VERSION 5.7 ;
  NOWIREEXTENSIONATPIN ON ;
  DIVIDERCHAR "/" ;
  BUSBITCHARS "[]" ;
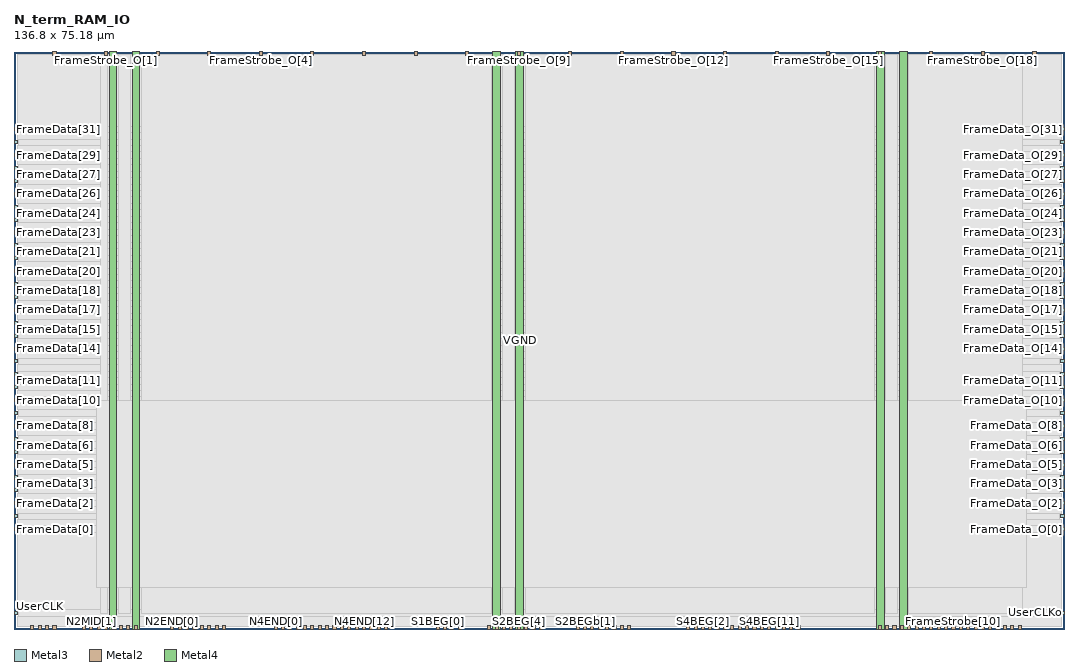
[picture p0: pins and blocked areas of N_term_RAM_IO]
MACRO N_term_RAM_IO
  CLASS BLOCK ;
  FOREIGN N_term_RAM_IO ;
  ORIGIN 0.000 0.000 ;
  SIZE 136.800 BY 75.180 ;
  PIN FrameData[0]
    DIRECTION INPUT ;
    USE SIGNAL ;
    ANTENNAGATEAREA 0.180700 ;
    PORT
      LAYER Metal3 ;
        RECT 0.000 12.820 0.400 13.220 ;
    END
  END FrameData[0]
  PIN FrameData[10]
    DIRECTION INPUT ;
    USE SIGNAL ;
    ANTENNAGATEAREA 0.180700 ;
    PORT
      LAYER Metal3 ;
        RECT 0.000 29.620 0.400 30.020 ;
    END
  END FrameData[10]
  PIN FrameData[11]
    DIRECTION INPUT ;
    USE SIGNAL ;
    ANTENNAGATEAREA 0.180700 ;
    PORT
      LAYER Metal3 ;
        RECT 0.000 31.300 0.400 31.700 ;
    END
  END FrameData[11]
  PIN FrameData[12]
    DIRECTION INPUT ;
    USE SIGNAL ;
    ANTENNAGATEAREA 0.180700 ;
    PORT
      LAYER Metal3 ;
        RECT 0.000 32.980 0.400 33.380 ;
    END
  END FrameData[12]
  PIN FrameData[13]
    DIRECTION INPUT ;
    USE SIGNAL ;
    ANTENNAGATEAREA 0.180700 ;
    PORT
      LAYER Metal3 ;
        RECT 0.000 34.660 0.400 35.060 ;
    END
  END FrameData[13]
  PIN FrameData[14]
    DIRECTION INPUT ;
    USE SIGNAL ;
    ANTENNAGATEAREA 0.180700 ;
    PORT
      LAYER Metal3 ;
        RECT 0.000 36.340 0.400 36.740 ;
    END
  END FrameData[14]
  PIN FrameData[15]
    DIRECTION INPUT ;
    USE SIGNAL ;
    ANTENNAGATEAREA 0.180700 ;
    PORT
      LAYER Metal3 ;
        RECT 0.000 38.020 0.400 38.420 ;
    END
  END FrameData[15]
  PIN FrameData[16]
    DIRECTION INPUT ;
    USE SIGNAL ;
    ANTENNAGATEAREA 0.180700 ;
    PORT
      LAYER Metal3 ;
        RECT 0.000 39.700 0.400 40.100 ;
    END
  END FrameData[16]
  PIN FrameData[17]
    DIRECTION INPUT ;
    USE SIGNAL ;
    ANTENNAGATEAREA 0.180700 ;
    PORT
      LAYER Metal3 ;
        RECT 0.000 41.380 0.400 41.780 ;
    END
  END FrameData[17]
  PIN FrameData[18]
    DIRECTION INPUT ;
    USE SIGNAL ;
    ANTENNAGATEAREA 0.180700 ;
    PORT
      LAYER Metal3 ;
        RECT 0.000 43.060 0.400 43.460 ;
    END
  END FrameData[18]
  PIN FrameData[19]
    DIRECTION INPUT ;
    USE SIGNAL ;
    ANTENNAGATEAREA 0.180700 ;
    PORT
      LAYER Metal3 ;
        RECT 0.000 44.740 0.400 45.140 ;
    END
  END FrameData[19]
  PIN FrameData[1]
    DIRECTION INPUT ;
    USE SIGNAL ;
    ANTENNAGATEAREA 0.180700 ;
    PORT
      LAYER Metal3 ;
        RECT 0.000 14.500 0.400 14.900 ;
    END
  END FrameData[1]
  PIN FrameData[20]
    DIRECTION INPUT ;
    USE SIGNAL ;
    ANTENNAGATEAREA 0.180700 ;
    PORT
      LAYER Metal3 ;
        RECT 0.000 46.420 0.400 46.820 ;
    END
  END FrameData[20]
  PIN FrameData[21]
    DIRECTION INPUT ;
    USE SIGNAL ;
    ANTENNAGATEAREA 0.180700 ;
    PORT
      LAYER Metal3 ;
        RECT 0.000 48.100 0.400 48.500 ;
    END
  END FrameData[21]
  PIN FrameData[22]
    DIRECTION INPUT ;
    USE SIGNAL ;
    ANTENNAGATEAREA 0.180700 ;
    PORT
      LAYER Metal3 ;
        RECT 0.000 49.780 0.400 50.180 ;
    END
  END FrameData[22]
  PIN FrameData[23]
    DIRECTION INPUT ;
    USE SIGNAL ;
    ANTENNAGATEAREA 0.180700 ;
    PORT
      LAYER Metal3 ;
        RECT 0.000 51.460 0.400 51.860 ;
    END
  END FrameData[23]
  PIN FrameData[24]
    DIRECTION INPUT ;
    USE SIGNAL ;
    ANTENNAGATEAREA 0.180700 ;
    PORT
      LAYER Metal3 ;
        RECT 0.000 53.140 0.400 53.540 ;
    END
  END FrameData[24]
  PIN FrameData[25]
    DIRECTION INPUT ;
    USE SIGNAL ;
    ANTENNAGATEAREA 0.180700 ;
    PORT
      LAYER Metal3 ;
        RECT 0.000 54.820 0.400 55.220 ;
    END
  END FrameData[25]
  PIN FrameData[26]
    DIRECTION INPUT ;
    USE SIGNAL ;
    ANTENNAGATEAREA 0.180700 ;
    PORT
      LAYER Metal3 ;
        RECT 0.000 56.500 0.400 56.900 ;
    END
  END FrameData[26]
  PIN FrameData[27]
    DIRECTION INPUT ;
    USE SIGNAL ;
    ANTENNAGATEAREA 0.180700 ;
    PORT
      LAYER Metal3 ;
        RECT 0.000 58.180 0.400 58.580 ;
    END
  END FrameData[27]
  PIN FrameData[28]
    DIRECTION INPUT ;
    USE SIGNAL ;
    ANTENNAGATEAREA 0.180700 ;
    PORT
      LAYER Metal3 ;
        RECT 0.000 59.860 0.400 60.260 ;
    END
  END FrameData[28]
  PIN FrameData[29]
    DIRECTION INPUT ;
    USE SIGNAL ;
    ANTENNAGATEAREA 0.180700 ;
    PORT
      LAYER Metal3 ;
        RECT 0.000 61.540 0.400 61.940 ;
    END
  END FrameData[29]
  PIN FrameData[2]
    DIRECTION INPUT ;
    USE SIGNAL ;
    ANTENNAGATEAREA 0.180700 ;
    PORT
      LAYER Metal3 ;
        RECT 0.000 16.180 0.400 16.580 ;
    END
  END FrameData[2]
  PIN FrameData[30]
    DIRECTION INPUT ;
    USE SIGNAL ;
    ANTENNAGATEAREA 0.180700 ;
    PORT
      LAYER Metal3 ;
        RECT 0.000 63.220 0.400 63.620 ;
    END
  END FrameData[30]
  PIN FrameData[31]
    DIRECTION INPUT ;
    USE SIGNAL ;
    ANTENNAGATEAREA 0.180700 ;
    PORT
      LAYER Metal3 ;
        RECT 0.000 64.900 0.400 65.300 ;
    END
  END FrameData[31]
  PIN FrameData[3]
    DIRECTION INPUT ;
    USE SIGNAL ;
    ANTENNAGATEAREA 0.180700 ;
    PORT
      LAYER Metal3 ;
        RECT 0.000 17.860 0.400 18.260 ;
    END
  END FrameData[3]
  PIN FrameData[4]
    DIRECTION INPUT ;
    USE SIGNAL ;
    ANTENNAGATEAREA 0.180700 ;
    PORT
      LAYER Metal3 ;
        RECT 0.000 19.540 0.400 19.940 ;
    END
  END FrameData[4]
  PIN FrameData[5]
    DIRECTION INPUT ;
    USE SIGNAL ;
    ANTENNAGATEAREA 0.180700 ;
    PORT
      LAYER Metal3 ;
        RECT 0.000 21.220 0.400 21.620 ;
    END
  END FrameData[5]
  PIN FrameData[6]
    DIRECTION INPUT ;
    USE SIGNAL ;
    ANTENNAGATEAREA 0.180700 ;
    PORT
      LAYER Metal3 ;
        RECT 0.000 22.900 0.400 23.300 ;
    END
  END FrameData[6]
  PIN FrameData[7]
    DIRECTION INPUT ;
    USE SIGNAL ;
    ANTENNAGATEAREA 0.180700 ;
    PORT
      LAYER Metal3 ;
        RECT 0.000 24.580 0.400 24.980 ;
    END
  END FrameData[7]
  PIN FrameData[8]
    DIRECTION INPUT ;
    USE SIGNAL ;
    ANTENNAGATEAREA 0.180700 ;
    PORT
      LAYER Metal3 ;
        RECT 0.000 26.260 0.400 26.660 ;
    END
  END FrameData[8]
  PIN FrameData[9]
    DIRECTION INPUT ;
    USE SIGNAL ;
    ANTENNAGATEAREA 0.180700 ;
    PORT
      LAYER Metal3 ;
        RECT 0.000 27.940 0.400 28.340 ;
    END
  END FrameData[9]
  PIN FrameData_O[0]
    DIRECTION OUTPUT ;
    USE SIGNAL ;
    ANTENNADIFFAREA 2.724000 ;
    PORT
      LAYER Metal3 ;
        RECT 136.400 12.820 136.800 13.220 ;
    END
  END FrameData_O[0]
  PIN FrameData_O[10]
    DIRECTION OUTPUT ;
    USE SIGNAL ;
    ANTENNADIFFAREA 2.724000 ;
    PORT
      LAYER Metal3 ;
        RECT 136.400 29.620 136.800 30.020 ;
    END
  END FrameData_O[10]
  PIN FrameData_O[11]
    DIRECTION OUTPUT ;
    USE SIGNAL ;
    ANTENNADIFFAREA 2.724000 ;
    PORT
      LAYER Metal3 ;
        RECT 136.400 31.300 136.800 31.700 ;
    END
  END FrameData_O[11]
  PIN FrameData_O[12]
    DIRECTION OUTPUT ;
    USE SIGNAL ;
    ANTENNADIFFAREA 2.724000 ;
    PORT
      LAYER Metal3 ;
        RECT 136.400 32.980 136.800 33.380 ;
    END
  END FrameData_O[12]
  PIN FrameData_O[13]
    DIRECTION OUTPUT ;
    USE SIGNAL ;
    ANTENNADIFFAREA 2.724000 ;
    PORT
      LAYER Metal3 ;
        RECT 136.400 34.660 136.800 35.060 ;
    END
  END FrameData_O[13]
  PIN FrameData_O[14]
    DIRECTION OUTPUT ;
    USE SIGNAL ;
    ANTENNADIFFAREA 2.724000 ;
    PORT
      LAYER Metal3 ;
        RECT 136.400 36.340 136.800 36.740 ;
    END
  END FrameData_O[14]
  PIN FrameData_O[15]
    DIRECTION OUTPUT ;
    USE SIGNAL ;
    ANTENNADIFFAREA 2.724000 ;
    PORT
      LAYER Metal3 ;
        RECT 136.400 38.020 136.800 38.420 ;
    END
  END FrameData_O[15]
  PIN FrameData_O[16]
    DIRECTION OUTPUT ;
    USE SIGNAL ;
    ANTENNADIFFAREA 2.724000 ;
    PORT
      LAYER Metal3 ;
        RECT 136.400 39.700 136.800 40.100 ;
    END
  END FrameData_O[16]
  PIN FrameData_O[17]
    DIRECTION OUTPUT ;
    USE SIGNAL ;
    ANTENNADIFFAREA 2.724000 ;
    PORT
      LAYER Metal3 ;
        RECT 136.400 41.380 136.800 41.780 ;
    END
  END FrameData_O[17]
  PIN FrameData_O[18]
    DIRECTION OUTPUT ;
    USE SIGNAL ;
    ANTENNADIFFAREA 2.724000 ;
    PORT
      LAYER Metal3 ;
        RECT 136.400 43.060 136.800 43.460 ;
    END
  END FrameData_O[18]
  PIN FrameData_O[19]
    DIRECTION OUTPUT ;
    USE SIGNAL ;
    ANTENNADIFFAREA 2.724000 ;
    PORT
      LAYER Metal3 ;
        RECT 136.400 44.740 136.800 45.140 ;
    END
  END FrameData_O[19]
  PIN FrameData_O[1]
    DIRECTION OUTPUT ;
    USE SIGNAL ;
    ANTENNADIFFAREA 2.724000 ;
    PORT
      LAYER Metal3 ;
        RECT 136.400 14.500 136.800 14.900 ;
    END
  END FrameData_O[1]
  PIN FrameData_O[20]
    DIRECTION OUTPUT ;
    USE SIGNAL ;
    ANTENNADIFFAREA 2.724000 ;
    PORT
      LAYER Metal3 ;
        RECT 136.400 46.420 136.800 46.820 ;
    END
  END FrameData_O[20]
  PIN FrameData_O[21]
    DIRECTION OUTPUT ;
    USE SIGNAL ;
    ANTENNADIFFAREA 2.724000 ;
    PORT
      LAYER Metal3 ;
        RECT 136.400 48.100 136.800 48.500 ;
    END
  END FrameData_O[21]
  PIN FrameData_O[22]
    DIRECTION OUTPUT ;
    USE SIGNAL ;
    ANTENNADIFFAREA 2.724000 ;
    PORT
      LAYER Metal3 ;
        RECT 136.400 49.780 136.800 50.180 ;
    END
  END FrameData_O[22]
  PIN FrameData_O[23]
    DIRECTION OUTPUT ;
    USE SIGNAL ;
    ANTENNADIFFAREA 2.724000 ;
    PORT
      LAYER Metal3 ;
        RECT 136.400 51.460 136.800 51.860 ;
    END
  END FrameData_O[23]
  PIN FrameData_O[24]
    DIRECTION OUTPUT ;
    USE SIGNAL ;
    ANTENNADIFFAREA 2.724000 ;
    PORT
      LAYER Metal3 ;
        RECT 136.400 53.140 136.800 53.540 ;
    END
  END FrameData_O[24]
  PIN FrameData_O[25]
    DIRECTION OUTPUT ;
    USE SIGNAL ;
    ANTENNADIFFAREA 2.724000 ;
    PORT
      LAYER Metal3 ;
        RECT 136.400 54.820 136.800 55.220 ;
    END
  END FrameData_O[25]
  PIN FrameData_O[26]
    DIRECTION OUTPUT ;
    USE SIGNAL ;
    ANTENNADIFFAREA 2.724000 ;
    PORT
      LAYER Metal3 ;
        RECT 136.400 56.500 136.800 56.900 ;
    END
  END FrameData_O[26]
  PIN FrameData_O[27]
    DIRECTION OUTPUT ;
    USE SIGNAL ;
    ANTENNADIFFAREA 2.724000 ;
    PORT
      LAYER Metal3 ;
        RECT 136.400 58.180 136.800 58.580 ;
    END
  END FrameData_O[27]
  PIN FrameData_O[28]
    DIRECTION OUTPUT ;
    USE SIGNAL ;
    ANTENNADIFFAREA 2.724000 ;
    PORT
      LAYER Metal3 ;
        RECT 136.400 59.860 136.800 60.260 ;
    END
  END FrameData_O[28]
  PIN FrameData_O[29]
    DIRECTION OUTPUT ;
    USE SIGNAL ;
    ANTENNADIFFAREA 2.724000 ;
    PORT
      LAYER Metal3 ;
        RECT 136.400 61.540 136.800 61.940 ;
    END
  END FrameData_O[29]
  PIN FrameData_O[2]
    DIRECTION OUTPUT ;
    USE SIGNAL ;
    ANTENNADIFFAREA 2.724000 ;
    PORT
      LAYER Metal3 ;
        RECT 136.400 16.180 136.800 16.580 ;
    END
  END FrameData_O[2]
  PIN FrameData_O[30]
    DIRECTION OUTPUT ;
    USE SIGNAL ;
    ANTENNADIFFAREA 2.724000 ;
    PORT
      LAYER Metal3 ;
        RECT 136.400 63.220 136.800 63.620 ;
    END
  END FrameData_O[30]
  PIN FrameData_O[31]
    DIRECTION OUTPUT ;
    USE SIGNAL ;
    ANTENNADIFFAREA 2.724000 ;
    PORT
      LAYER Metal3 ;
        RECT 136.400 64.900 136.800 65.300 ;
    END
  END FrameData_O[31]
  PIN FrameData_O[3]
    DIRECTION OUTPUT ;
    USE SIGNAL ;
    ANTENNADIFFAREA 2.724000 ;
    PORT
      LAYER Metal3 ;
        RECT 136.400 17.860 136.800 18.260 ;
    END
  END FrameData_O[3]
  PIN FrameData_O[4]
    DIRECTION OUTPUT ;
    USE SIGNAL ;
    ANTENNADIFFAREA 2.724000 ;
    PORT
      LAYER Metal3 ;
        RECT 136.400 19.540 136.800 19.940 ;
    END
  END FrameData_O[4]
  PIN FrameData_O[5]
    DIRECTION OUTPUT ;
    USE SIGNAL ;
    ANTENNADIFFAREA 2.724000 ;
    PORT
      LAYER Metal3 ;
        RECT 136.400 21.220 136.800 21.620 ;
    END
  END FrameData_O[5]
  PIN FrameData_O[6]
    DIRECTION OUTPUT ;
    USE SIGNAL ;
    ANTENNADIFFAREA 2.724000 ;
    PORT
      LAYER Metal3 ;
        RECT 136.400 22.900 136.800 23.300 ;
    END
  END FrameData_O[6]
  PIN FrameData_O[7]
    DIRECTION OUTPUT ;
    USE SIGNAL ;
    ANTENNADIFFAREA 2.724000 ;
    PORT
      LAYER Metal3 ;
        RECT 136.400 24.580 136.800 24.980 ;
    END
  END FrameData_O[7]
  PIN FrameData_O[8]
    DIRECTION OUTPUT ;
    USE SIGNAL ;
    ANTENNADIFFAREA 2.724000 ;
    PORT
      LAYER Metal3 ;
        RECT 136.400 26.260 136.800 26.660 ;
    END
  END FrameData_O[8]
  PIN FrameData_O[9]
    DIRECTION OUTPUT ;
    USE SIGNAL ;
    ANTENNADIFFAREA 2.724000 ;
    PORT
      LAYER Metal3 ;
        RECT 136.400 27.940 136.800 28.340 ;
    END
  END FrameData_O[9]
  PIN FrameStrobe[0]
    DIRECTION INPUT ;
    USE SIGNAL ;
    ANTENNAGATEAREA 0.180700 ;
    PORT
      LAYER Metal2 ;
        RECT 112.600 0.000 113.000 0.400 ;
    END
  END FrameStrobe[0]
  PIN FrameStrobe[10]
    DIRECTION INPUT ;
    USE SIGNAL ;
    ANTENNAGATEAREA 0.180700 ;
    PORT
      LAYER Metal2 ;
        RECT 122.200 0.000 122.600 0.400 ;
    END
  END FrameStrobe[10]
  PIN FrameStrobe[11]
    DIRECTION INPUT ;
    USE SIGNAL ;
    ANTENNAGATEAREA 0.180700 ;
    PORT
      LAYER Metal2 ;
        RECT 123.160 0.000 123.560 0.400 ;
    END
  END FrameStrobe[11]
  PIN FrameStrobe[12]
    DIRECTION INPUT ;
    USE SIGNAL ;
    ANTENNAGATEAREA 0.180700 ;
    PORT
      LAYER Metal2 ;
        RECT 124.120 0.000 124.520 0.400 ;
    END
  END FrameStrobe[12]
  PIN FrameStrobe[13]
    DIRECTION INPUT ;
    USE SIGNAL ;
    ANTENNAGATEAREA 0.180700 ;
    PORT
      LAYER Metal2 ;
        RECT 125.080 0.000 125.480 0.400 ;
    END
  END FrameStrobe[13]
  PIN FrameStrobe[14]
    DIRECTION INPUT ;
    USE SIGNAL ;
    ANTENNAGATEAREA 0.180700 ;
    PORT
      LAYER Metal2 ;
        RECT 126.040 0.000 126.440 0.400 ;
    END
  END FrameStrobe[14]
  PIN FrameStrobe[15]
    DIRECTION INPUT ;
    USE SIGNAL ;
    ANTENNAGATEAREA 0.180700 ;
    PORT
      LAYER Metal2 ;
        RECT 127.000 0.000 127.400 0.400 ;
    END
  END FrameStrobe[15]
  PIN FrameStrobe[16]
    DIRECTION INPUT ;
    USE SIGNAL ;
    ANTENNAGATEAREA 0.180700 ;
    PORT
      LAYER Metal2 ;
        RECT 127.960 0.000 128.360 0.400 ;
    END
  END FrameStrobe[16]
  PIN FrameStrobe[17]
    DIRECTION INPUT ;
    USE SIGNAL ;
    ANTENNAGATEAREA 0.180700 ;
    PORT
      LAYER Metal2 ;
        RECT 128.920 0.000 129.320 0.400 ;
    END
  END FrameStrobe[17]
  PIN FrameStrobe[18]
    DIRECTION INPUT ;
    USE SIGNAL ;
    ANTENNAGATEAREA 0.180700 ;
    PORT
      LAYER Metal2 ;
        RECT 129.880 0.000 130.280 0.400 ;
    END
  END FrameStrobe[18]
  PIN FrameStrobe[19]
    DIRECTION INPUT ;
    USE SIGNAL ;
    ANTENNAGATEAREA 0.180700 ;
    PORT
      LAYER Metal2 ;
        RECT 130.840 0.000 131.240 0.400 ;
    END
  END FrameStrobe[19]
  PIN FrameStrobe[1]
    DIRECTION INPUT ;
    USE SIGNAL ;
    ANTENNAGATEAREA 0.180700 ;
    PORT
      LAYER Metal2 ;
        RECT 113.560 0.000 113.960 0.400 ;
    END
  END FrameStrobe[1]
  PIN FrameStrobe[2]
    DIRECTION INPUT ;
    USE SIGNAL ;
    ANTENNAGATEAREA 0.180700 ;
    PORT
      LAYER Metal2 ;
        RECT 114.520 0.000 114.920 0.400 ;
    END
  END FrameStrobe[2]
  PIN FrameStrobe[3]
    DIRECTION INPUT ;
    USE SIGNAL ;
    ANTENNAGATEAREA 0.180700 ;
    PORT
      LAYER Metal2 ;
        RECT 115.480 0.000 115.880 0.400 ;
    END
  END FrameStrobe[3]
  PIN FrameStrobe[4]
    DIRECTION INPUT ;
    USE SIGNAL ;
    ANTENNAGATEAREA 0.180700 ;
    PORT
      LAYER Metal2 ;
        RECT 116.440 0.000 116.840 0.400 ;
    END
  END FrameStrobe[4]
  PIN FrameStrobe[5]
    DIRECTION INPUT ;
    USE SIGNAL ;
    ANTENNAGATEAREA 0.180700 ;
    PORT
      LAYER Metal2 ;
        RECT 117.400 0.000 117.800 0.400 ;
    END
  END FrameStrobe[5]
  PIN FrameStrobe[6]
    DIRECTION INPUT ;
    USE SIGNAL ;
    ANTENNAGATEAREA 0.180700 ;
    PORT
      LAYER Metal2 ;
        RECT 118.360 0.000 118.760 0.400 ;
    END
  END FrameStrobe[6]
  PIN FrameStrobe[7]
    DIRECTION INPUT ;
    USE SIGNAL ;
    ANTENNAGATEAREA 0.180700 ;
    PORT
      LAYER Metal2 ;
        RECT 119.320 0.000 119.720 0.400 ;
    END
  END FrameStrobe[7]
  PIN FrameStrobe[8]
    DIRECTION INPUT ;
    USE SIGNAL ;
    ANTENNAGATEAREA 0.180700 ;
    PORT
      LAYER Metal2 ;
        RECT 120.280 0.000 120.680 0.400 ;
    END
  END FrameStrobe[8]
  PIN FrameStrobe[9]
    DIRECTION INPUT ;
    USE SIGNAL ;
    ANTENNAGATEAREA 0.180700 ;
    PORT
      LAYER Metal2 ;
        RECT 121.240 0.000 121.640 0.400 ;
    END
  END FrameStrobe[9]
  PIN FrameStrobe_O[0]
    DIRECTION OUTPUT ;
    USE SIGNAL ;
    ANTENNADIFFAREA 2.724000 ;
    PORT
      LAYER Metal2 ;
        RECT 5.080 74.780 5.480 75.180 ;
    END
  END FrameStrobe_O[0]
  PIN FrameStrobe_O[10]
    DIRECTION OUTPUT ;
    USE SIGNAL ;
    ANTENNADIFFAREA 2.724000 ;
    PORT
      LAYER Metal2 ;
        RECT 72.280 74.780 72.680 75.180 ;
    END
  END FrameStrobe_O[10]
  PIN FrameStrobe_O[11]
    DIRECTION OUTPUT ;
    USE SIGNAL ;
    ANTENNADIFFAREA 2.724000 ;
    PORT
      LAYER Metal2 ;
        RECT 79.000 74.780 79.400 75.180 ;
    END
  END FrameStrobe_O[11]
  PIN FrameStrobe_O[12]
    DIRECTION OUTPUT ;
    USE SIGNAL ;
    ANTENNADIFFAREA 2.724000 ;
    PORT
      LAYER Metal2 ;
        RECT 85.720 74.780 86.120 75.180 ;
    END
  END FrameStrobe_O[12]
  PIN FrameStrobe_O[13]
    DIRECTION OUTPUT ;
    USE SIGNAL ;
    ANTENNADIFFAREA 2.724000 ;
    PORT
      LAYER Metal2 ;
        RECT 92.440 74.780 92.840 75.180 ;
    END
  END FrameStrobe_O[13]
  PIN FrameStrobe_O[14]
    DIRECTION OUTPUT ;
    USE SIGNAL ;
    ANTENNADIFFAREA 2.724000 ;
    PORT
      LAYER Metal2 ;
        RECT 99.160 74.780 99.560 75.180 ;
    END
  END FrameStrobe_O[14]
  PIN FrameStrobe_O[15]
    DIRECTION OUTPUT ;
    USE SIGNAL ;
    ANTENNADIFFAREA 2.724000 ;
    PORT
      LAYER Metal2 ;
        RECT 105.880 74.780 106.280 75.180 ;
    END
  END FrameStrobe_O[15]
  PIN FrameStrobe_O[16]
    DIRECTION OUTPUT ;
    USE SIGNAL ;
    ANTENNADIFFAREA 2.724000 ;
    PORT
      LAYER Metal2 ;
        RECT 112.600 74.780 113.000 75.180 ;
    END
  END FrameStrobe_O[16]
  PIN FrameStrobe_O[17]
    DIRECTION OUTPUT ;
    USE SIGNAL ;
    ANTENNADIFFAREA 2.724000 ;
    PORT
      LAYER Metal2 ;
        RECT 119.320 74.780 119.720 75.180 ;
    END
  END FrameStrobe_O[17]
  PIN FrameStrobe_O[18]
    DIRECTION OUTPUT ;
    USE SIGNAL ;
    ANTENNADIFFAREA 2.724000 ;
    PORT
      LAYER Metal2 ;
        RECT 126.040 74.780 126.440 75.180 ;
    END
  END FrameStrobe_O[18]
  PIN FrameStrobe_O[19]
    DIRECTION OUTPUT ;
    USE SIGNAL ;
    ANTENNADIFFAREA 2.724000 ;
    PORT
      LAYER Metal2 ;
        RECT 132.760 74.780 133.160 75.180 ;
    END
  END FrameStrobe_O[19]
  PIN FrameStrobe_O[1]
    DIRECTION OUTPUT ;
    USE SIGNAL ;
    ANTENNADIFFAREA 2.724000 ;
    PORT
      LAYER Metal2 ;
        RECT 11.800 74.780 12.200 75.180 ;
    END
  END FrameStrobe_O[1]
  PIN FrameStrobe_O[2]
    DIRECTION OUTPUT ;
    USE SIGNAL ;
    ANTENNADIFFAREA 2.724000 ;
    PORT
      LAYER Metal2 ;
        RECT 18.520 74.780 18.920 75.180 ;
    END
  END FrameStrobe_O[2]
  PIN FrameStrobe_O[3]
    DIRECTION OUTPUT ;
    USE SIGNAL ;
    ANTENNADIFFAREA 2.724000 ;
    PORT
      LAYER Metal2 ;
        RECT 25.240 74.780 25.640 75.180 ;
    END
  END FrameStrobe_O[3]
  PIN FrameStrobe_O[4]
    DIRECTION OUTPUT ;
    USE SIGNAL ;
    ANTENNADIFFAREA 2.724000 ;
    PORT
      LAYER Metal2 ;
        RECT 31.960 74.780 32.360 75.180 ;
    END
  END FrameStrobe_O[4]
  PIN FrameStrobe_O[5]
    DIRECTION OUTPUT ;
    USE SIGNAL ;
    ANTENNADIFFAREA 2.724000 ;
    PORT
      LAYER Metal2 ;
        RECT 38.680 74.780 39.080 75.180 ;
    END
  END FrameStrobe_O[5]
  PIN FrameStrobe_O[6]
    DIRECTION OUTPUT ;
    USE SIGNAL ;
    ANTENNADIFFAREA 2.724000 ;
    PORT
      LAYER Metal2 ;
        RECT 45.400 74.780 45.800 75.180 ;
    END
  END FrameStrobe_O[6]
  PIN FrameStrobe_O[7]
    DIRECTION OUTPUT ;
    USE SIGNAL ;
    ANTENNADIFFAREA 2.724000 ;
    PORT
      LAYER Metal2 ;
        RECT 52.120 74.780 52.520 75.180 ;
    END
  END FrameStrobe_O[7]
  PIN FrameStrobe_O[8]
    DIRECTION OUTPUT ;
    USE SIGNAL ;
    ANTENNADIFFAREA 2.724000 ;
    PORT
      LAYER Metal2 ;
        RECT 58.840 74.780 59.240 75.180 ;
    END
  END FrameStrobe_O[8]
  PIN FrameStrobe_O[9]
    DIRECTION OUTPUT ;
    USE SIGNAL ;
    ANTENNADIFFAREA 2.724000 ;
    PORT
      LAYER Metal2 ;
        RECT 65.560 74.780 65.960 75.180 ;
    END
  END FrameStrobe_O[9]
  PIN N1END[0]
    DIRECTION INPUT ;
    USE SIGNAL ;
    ANTENNAGATEAREA 0.180700 ;
    PORT
      LAYER Metal2 ;
        RECT 2.200 0.000 2.600 0.400 ;
    END
  END N1END[0]
  PIN N1END[1]
    DIRECTION INPUT ;
    USE SIGNAL ;
    ANTENNAGATEAREA 0.180700 ;
    PORT
      LAYER Metal2 ;
        RECT 3.160 0.000 3.560 0.400 ;
    END
  END N1END[1]
  PIN N1END[2]
    DIRECTION INPUT ;
    USE SIGNAL ;
    ANTENNAGATEAREA 0.180700 ;
    PORT
      LAYER Metal2 ;
        RECT 4.120 0.000 4.520 0.400 ;
    END
  END N1END[2]
  PIN N1END[3]
    DIRECTION INPUT ;
    USE SIGNAL ;
    ANTENNAGATEAREA 0.180700 ;
    PORT
      LAYER Metal2 ;
        RECT 5.080 0.000 5.480 0.400 ;
    END
  END N1END[3]
  PIN N2END[0]
    DIRECTION INPUT ;
    USE SIGNAL ;
    ANTENNAGATEAREA 0.180700 ;
    PORT
      LAYER Metal2 ;
        RECT 20.440 0.000 20.840 0.400 ;
    END
  END N2END[0]
  PIN N2END[1]
    DIRECTION INPUT ;
    USE SIGNAL ;
    ANTENNAGATEAREA 0.180700 ;
    PORT
      LAYER Metal2 ;
        RECT 21.400 0.000 21.800 0.400 ;
    END
  END N2END[1]
  PIN N2END[2]
    DIRECTION INPUT ;
    USE SIGNAL ;
    ANTENNAGATEAREA 0.180700 ;
    PORT
      LAYER Metal2 ;
        RECT 22.360 0.000 22.760 0.400 ;
    END
  END N2END[2]
  PIN N2END[3]
    DIRECTION INPUT ;
    USE SIGNAL ;
    ANTENNAGATEAREA 0.180700 ;
    PORT
      LAYER Metal2 ;
        RECT 23.320 0.000 23.720 0.400 ;
    END
  END N2END[3]
  PIN N2END[4]
    DIRECTION INPUT ;
    USE SIGNAL ;
    ANTENNAGATEAREA 0.180700 ;
    PORT
      LAYER Metal2 ;
        RECT 24.280 0.000 24.680 0.400 ;
    END
  END N2END[4]
  PIN N2END[5]
    DIRECTION INPUT ;
    USE SIGNAL ;
    ANTENNAGATEAREA 0.180700 ;
    PORT
      LAYER Metal2 ;
        RECT 25.240 0.000 25.640 0.400 ;
    END
  END N2END[5]
  PIN N2END[6]
    DIRECTION INPUT ;
    USE SIGNAL ;
    ANTENNAGATEAREA 0.180700 ;
    PORT
      LAYER Metal2 ;
        RECT 26.200 0.000 26.600 0.400 ;
    END
  END N2END[6]
  PIN N2END[7]
    DIRECTION INPUT ;
    USE SIGNAL ;
    ANTENNAGATEAREA 0.180700 ;
    PORT
      LAYER Metal2 ;
        RECT 27.160 0.000 27.560 0.400 ;
    END
  END N2END[7]
  PIN N2MID[0]
    DIRECTION INPUT ;
    USE SIGNAL ;
    ANTENNAGATEAREA 0.180700 ;
    PORT
      LAYER Metal2 ;
        RECT 8.920 0.000 9.320 0.400 ;
    END
  END N2MID[0]
  PIN N2MID[1]
    DIRECTION INPUT ;
    USE SIGNAL ;
    ANTENNAGATEAREA 0.180700 ;
    PORT
      LAYER Metal2 ;
        RECT 9.880 0.000 10.280 0.400 ;
    END
  END N2MID[1]
  PIN N2MID[2]
    DIRECTION INPUT ;
    USE SIGNAL ;
    ANTENNAGATEAREA 0.180700 ;
    PORT
      LAYER Metal2 ;
        RECT 10.840 0.000 11.240 0.400 ;
    END
  END N2MID[2]
  PIN N2MID[3]
    DIRECTION INPUT ;
    USE SIGNAL ;
    ANTENNAGATEAREA 0.180700 ;
    PORT
      LAYER Metal2 ;
        RECT 11.800 0.000 12.200 0.400 ;
    END
  END N2MID[3]
  PIN N2MID[4]
    DIRECTION INPUT ;
    USE SIGNAL ;
    ANTENNAGATEAREA 0.180700 ;
    PORT
      LAYER Metal2 ;
        RECT 12.760 0.000 13.160 0.400 ;
    END
  END N2MID[4]
  PIN N2MID[5]
    DIRECTION INPUT ;
    USE SIGNAL ;
    ANTENNAGATEAREA 0.180700 ;
    PORT
      LAYER Metal2 ;
        RECT 13.720 0.000 14.120 0.400 ;
    END
  END N2MID[5]
  PIN N2MID[6]
    DIRECTION INPUT ;
    USE SIGNAL ;
    ANTENNAGATEAREA 0.180700 ;
    PORT
      LAYER Metal2 ;
        RECT 14.680 0.000 15.080 0.400 ;
    END
  END N2MID[6]
  PIN N2MID[7]
    DIRECTION INPUT ;
    USE SIGNAL ;
    ANTENNAGATEAREA 0.180700 ;
    PORT
      LAYER Metal2 ;
        RECT 15.640 0.000 16.040 0.400 ;
    END
  END N2MID[7]
  PIN N4END[0]
    DIRECTION INPUT ;
    USE SIGNAL ;
    ANTENNAGATEAREA 0.180700 ;
    PORT
      LAYER Metal2 ;
        RECT 33.880 0.000 34.280 0.400 ;
    END
  END N4END[0]
  PIN N4END[10]
    DIRECTION INPUT ;
    USE SIGNAL ;
    ANTENNAGATEAREA 0.180700 ;
    PORT
      LAYER Metal2 ;
        RECT 43.480 0.000 43.880 0.400 ;
    END
  END N4END[10]
  PIN N4END[11]
    DIRECTION INPUT ;
    USE SIGNAL ;
    ANTENNAGATEAREA 0.180700 ;
    PORT
      LAYER Metal2 ;
        RECT 44.440 0.000 44.840 0.400 ;
    END
  END N4END[11]
  PIN N4END[12]
    DIRECTION INPUT ;
    USE SIGNAL ;
    ANTENNAGATEAREA 0.180700 ;
    PORT
      LAYER Metal2 ;
        RECT 45.400 0.000 45.800 0.400 ;
    END
  END N4END[12]
  PIN N4END[13]
    DIRECTION INPUT ;
    USE SIGNAL ;
    ANTENNAGATEAREA 0.180700 ;
    PORT
      LAYER Metal2 ;
        RECT 46.360 0.000 46.760 0.400 ;
    END
  END N4END[13]
  PIN N4END[14]
    DIRECTION INPUT ;
    USE SIGNAL ;
    ANTENNAGATEAREA 0.180700 ;
    PORT
      LAYER Metal2 ;
        RECT 47.320 0.000 47.720 0.400 ;
    END
  END N4END[14]
  PIN N4END[15]
    DIRECTION INPUT ;
    USE SIGNAL ;
    ANTENNAGATEAREA 0.180700 ;
    PORT
      LAYER Metal2 ;
        RECT 48.280 0.000 48.680 0.400 ;
    END
  END N4END[15]
  PIN N4END[1]
    DIRECTION INPUT ;
    USE SIGNAL ;
    ANTENNAGATEAREA 0.180700 ;
    PORT
      LAYER Metal2 ;
        RECT 34.840 0.000 35.240 0.400 ;
    END
  END N4END[1]
  PIN N4END[2]
    DIRECTION INPUT ;
    USE SIGNAL ;
    ANTENNAGATEAREA 0.180700 ;
    PORT
      LAYER Metal2 ;
        RECT 35.800 0.000 36.200 0.400 ;
    END
  END N4END[2]
  PIN N4END[3]
    DIRECTION INPUT ;
    USE SIGNAL ;
    ANTENNAGATEAREA 0.180700 ;
    PORT
      LAYER Metal2 ;
        RECT 36.760 0.000 37.160 0.400 ;
    END
  END N4END[3]
  PIN N4END[4]
    DIRECTION INPUT ;
    USE SIGNAL ;
    ANTENNAGATEAREA 0.180700 ;
    PORT
      LAYER Metal2 ;
        RECT 37.720 0.000 38.120 0.400 ;
    END
  END N4END[4]
  PIN N4END[5]
    DIRECTION INPUT ;
    USE SIGNAL ;
    ANTENNAGATEAREA 0.180700 ;
    PORT
      LAYER Metal2 ;
        RECT 38.680 0.000 39.080 0.400 ;
    END
  END N4END[5]
  PIN N4END[6]
    DIRECTION INPUT ;
    USE SIGNAL ;
    ANTENNAGATEAREA 0.180700 ;
    PORT
      LAYER Metal2 ;
        RECT 39.640 0.000 40.040 0.400 ;
    END
  END N4END[6]
  PIN N4END[7]
    DIRECTION INPUT ;
    USE SIGNAL ;
    ANTENNAGATEAREA 0.180700 ;
    PORT
      LAYER Metal2 ;
        RECT 40.600 0.000 41.000 0.400 ;
    END
  END N4END[7]
  PIN N4END[8]
    DIRECTION INPUT ;
    USE SIGNAL ;
    ANTENNAGATEAREA 0.180700 ;
    PORT
      LAYER Metal2 ;
        RECT 41.560 0.000 41.960 0.400 ;
    END
  END N4END[8]
  PIN N4END[9]
    DIRECTION INPUT ;
    USE SIGNAL ;
    ANTENNAGATEAREA 0.180700 ;
    PORT
      LAYER Metal2 ;
        RECT 42.520 0.000 42.920 0.400 ;
    END
  END N4END[9]
  PIN S1BEG[0]
    DIRECTION OUTPUT ;
    USE SIGNAL ;
    ANTENNADIFFAREA 2.724000 ;
    PORT
      LAYER Metal2 ;
        RECT 55.000 0.000 55.400 0.400 ;
    END
  END S1BEG[0]
  PIN S1BEG[1]
    DIRECTION OUTPUT ;
    USE SIGNAL ;
    ANTENNADIFFAREA 2.724000 ;
    PORT
      LAYER Metal2 ;
        RECT 55.960 0.000 56.360 0.400 ;
    END
  END S1BEG[1]
  PIN S1BEG[2]
    DIRECTION OUTPUT ;
    USE SIGNAL ;
    ANTENNADIFFAREA 2.724000 ;
    PORT
      LAYER Metal2 ;
        RECT 56.920 0.000 57.320 0.400 ;
    END
  END S1BEG[2]
  PIN S1BEG[3]
    DIRECTION OUTPUT ;
    USE SIGNAL ;
    ANTENNADIFFAREA 2.724000 ;
    PORT
      LAYER Metal2 ;
        RECT 57.880 0.000 58.280 0.400 ;
    END
  END S1BEG[3]
  PIN S2BEG[0]
    DIRECTION OUTPUT ;
    USE SIGNAL ;
    ANTENNADIFFAREA 2.724000 ;
    PORT
      LAYER Metal2 ;
        RECT 61.720 0.000 62.120 0.400 ;
    END
  END S2BEG[0]
  PIN S2BEG[1]
    DIRECTION OUTPUT ;
    USE SIGNAL ;
    ANTENNADIFFAREA 2.724000 ;
    PORT
      LAYER Metal2 ;
        RECT 62.680 0.000 63.080 0.400 ;
    END
  END S2BEG[1]
  PIN S2BEG[2]
    DIRECTION OUTPUT ;
    USE SIGNAL ;
    ANTENNADIFFAREA 2.724000 ;
    PORT
      LAYER Metal2 ;
        RECT 63.640 0.000 64.040 0.400 ;
    END
  END S2BEG[2]
  PIN S2BEG[3]
    DIRECTION OUTPUT ;
    USE SIGNAL ;
    ANTENNADIFFAREA 2.724000 ;
    PORT
      LAYER Metal2 ;
        RECT 64.600 0.000 65.000 0.400 ;
    END
  END S2BEG[3]
  PIN S2BEG[4]
    DIRECTION OUTPUT ;
    USE SIGNAL ;
    ANTENNADIFFAREA 2.724000 ;
    PORT
      LAYER Metal2 ;
        RECT 65.560 0.000 65.960 0.400 ;
    END
  END S2BEG[4]
  PIN S2BEG[5]
    DIRECTION OUTPUT ;
    USE SIGNAL ;
    ANTENNADIFFAREA 2.724000 ;
    PORT
      LAYER Metal2 ;
        RECT 66.520 0.000 66.920 0.400 ;
    END
  END S2BEG[5]
  PIN S2BEG[6]
    DIRECTION OUTPUT ;
    USE SIGNAL ;
    ANTENNADIFFAREA 2.724000 ;
    PORT
      LAYER Metal2 ;
        RECT 67.480 0.000 67.880 0.400 ;
    END
  END S2BEG[6]
  PIN S2BEG[7]
    DIRECTION OUTPUT ;
    USE SIGNAL ;
    ANTENNADIFFAREA 2.724000 ;
    PORT
      LAYER Metal2 ;
        RECT 68.440 0.000 68.840 0.400 ;
    END
  END S2BEG[7]
  PIN S2BEGb[0]
    DIRECTION OUTPUT ;
    USE SIGNAL ;
    ANTENNADIFFAREA 2.724000 ;
    PORT
      LAYER Metal2 ;
        RECT 73.240 0.000 73.640 0.400 ;
    END
  END S2BEGb[0]
  PIN S2BEGb[1]
    DIRECTION OUTPUT ;
    USE SIGNAL ;
    ANTENNADIFFAREA 2.724000 ;
    PORT
      LAYER Metal2 ;
        RECT 74.200 0.000 74.600 0.400 ;
    END
  END S2BEGb[1]
  PIN S2BEGb[2]
    DIRECTION OUTPUT ;
    USE SIGNAL ;
    ANTENNADIFFAREA 2.724000 ;
    PORT
      LAYER Metal2 ;
        RECT 75.160 0.000 75.560 0.400 ;
    END
  END S2BEGb[2]
  PIN S2BEGb[3]
    DIRECTION OUTPUT ;
    USE SIGNAL ;
    ANTENNADIFFAREA 2.724000 ;
    PORT
      LAYER Metal2 ;
        RECT 76.120 0.000 76.520 0.400 ;
    END
  END S2BEGb[3]
  PIN S2BEGb[4]
    DIRECTION OUTPUT ;
    USE SIGNAL ;
    ANTENNADIFFAREA 2.724000 ;
    PORT
      LAYER Metal2 ;
        RECT 77.080 0.000 77.480 0.400 ;
    END
  END S2BEGb[4]
  PIN S2BEGb[5]
    DIRECTION OUTPUT ;
    USE SIGNAL ;
    ANTENNADIFFAREA 2.724000 ;
    PORT
      LAYER Metal2 ;
        RECT 78.040 0.000 78.440 0.400 ;
    END
  END S2BEGb[5]
  PIN S2BEGb[6]
    DIRECTION OUTPUT ;
    USE SIGNAL ;
    ANTENNADIFFAREA 2.724000 ;
    PORT
      LAYER Metal2 ;
        RECT 79.000 0.000 79.400 0.400 ;
    END
  END S2BEGb[6]
  PIN S2BEGb[7]
    DIRECTION OUTPUT ;
    USE SIGNAL ;
    ANTENNADIFFAREA 2.724000 ;
    PORT
      LAYER Metal2 ;
        RECT 79.960 0.000 80.360 0.400 ;
    END
  END S2BEGb[7]
  PIN S4BEG[0]
    DIRECTION OUTPUT ;
    USE SIGNAL ;
    ANTENNADIFFAREA 2.724000 ;
    PORT
      LAYER Metal2 ;
        RECT 87.640 0.000 88.040 0.400 ;
    END
  END S4BEG[0]
  PIN S4BEG[10]
    DIRECTION OUTPUT ;
    USE SIGNAL ;
    ANTENNADIFFAREA 2.724000 ;
    PORT
      LAYER Metal2 ;
        RECT 97.240 0.000 97.640 0.400 ;
    END
  END S4BEG[10]
  PIN S4BEG[11]
    DIRECTION OUTPUT ;
    USE SIGNAL ;
    ANTENNADIFFAREA 2.724000 ;
    PORT
      LAYER Metal2 ;
        RECT 98.200 0.000 98.600 0.400 ;
    END
  END S4BEG[11]
  PIN S4BEG[12]
    DIRECTION OUTPUT ;
    USE SIGNAL ;
    ANTENNADIFFAREA 2.724000 ;
    PORT
      LAYER Metal2 ;
        RECT 99.160 0.000 99.560 0.400 ;
    END
  END S4BEG[12]
  PIN S4BEG[13]
    DIRECTION OUTPUT ;
    USE SIGNAL ;
    ANTENNADIFFAREA 2.724000 ;
    PORT
      LAYER Metal2 ;
        RECT 100.120 0.000 100.520 0.400 ;
    END
  END S4BEG[13]
  PIN S4BEG[14]
    DIRECTION OUTPUT ;
    USE SIGNAL ;
    ANTENNADIFFAREA 2.724000 ;
    PORT
      LAYER Metal2 ;
        RECT 101.080 0.000 101.480 0.400 ;
    END
  END S4BEG[14]
  PIN S4BEG[15]
    DIRECTION OUTPUT ;
    USE SIGNAL ;
    ANTENNADIFFAREA 2.724000 ;
    PORT
      LAYER Metal2 ;
        RECT 102.040 0.000 102.440 0.400 ;
    END
  END S4BEG[15]
  PIN S4BEG[1]
    DIRECTION OUTPUT ;
    USE SIGNAL ;
    ANTENNADIFFAREA 2.724000 ;
    PORT
      LAYER Metal2 ;
        RECT 88.600 0.000 89.000 0.400 ;
    END
  END S4BEG[1]
  PIN S4BEG[2]
    DIRECTION OUTPUT ;
    USE SIGNAL ;
    ANTENNADIFFAREA 2.724000 ;
    PORT
      LAYER Metal2 ;
        RECT 89.560 0.000 89.960 0.400 ;
    END
  END S4BEG[2]
  PIN S4BEG[3]
    DIRECTION OUTPUT ;
    USE SIGNAL ;
    ANTENNADIFFAREA 2.724000 ;
    PORT
      LAYER Metal2 ;
        RECT 90.520 0.000 90.920 0.400 ;
    END
  END S4BEG[3]
  PIN S4BEG[4]
    DIRECTION OUTPUT ;
    USE SIGNAL ;
    ANTENNADIFFAREA 2.724000 ;
    PORT
      LAYER Metal2 ;
        RECT 91.480 0.000 91.880 0.400 ;
    END
  END S4BEG[4]
  PIN S4BEG[5]
    DIRECTION OUTPUT ;
    USE SIGNAL ;
    ANTENNADIFFAREA 2.724000 ;
    PORT
      LAYER Metal2 ;
        RECT 92.440 0.000 92.840 0.400 ;
    END
  END S4BEG[5]
  PIN S4BEG[6]
    DIRECTION OUTPUT ;
    USE SIGNAL ;
    ANTENNADIFFAREA 2.724000 ;
    PORT
      LAYER Metal2 ;
        RECT 93.400 0.000 93.800 0.400 ;
    END
  END S4BEG[6]
  PIN S4BEG[7]
    DIRECTION OUTPUT ;
    USE SIGNAL ;
    ANTENNADIFFAREA 2.724000 ;
    PORT
      LAYER Metal2 ;
        RECT 94.360 0.000 94.760 0.400 ;
    END
  END S4BEG[7]
  PIN S4BEG[8]
    DIRECTION OUTPUT ;
    USE SIGNAL ;
    ANTENNADIFFAREA 2.724000 ;
    PORT
      LAYER Metal2 ;
        RECT 95.320 0.000 95.720 0.400 ;
    END
  END S4BEG[8]
  PIN S4BEG[9]
    DIRECTION OUTPUT ;
    USE SIGNAL ;
    ANTENNADIFFAREA 2.724000 ;
    PORT
      LAYER Metal2 ;
        RECT 96.280 0.000 96.680 0.400 ;
    END
  END S4BEG[9]
  PIN UserCLK
    DIRECTION INPUT ;
    USE SIGNAL ;
    ANTENNAGATEAREA 0.180700 ;
    PORT
      LAYER Metal3 ;
        RECT 0.000 1.900 0.400 2.300 ;
    END
  END UserCLK
  PIN UserCLKo
    DIRECTION OUTPUT ;
    USE SIGNAL ;
    ANTENNADIFFAREA 2.724000 ;
    PORT
      LAYER Metal3 ;
        RECT 136.400 1.900 136.800 2.300 ;
    END
  END UserCLKo
  PIN VGND
    DIRECTION INOUT ;
    USE GROUND ;
    PORT
      LAYER Metal4 ;
        RECT 15.380 0.000 16.380 75.180 ;
    END
    PORT
      LAYER Metal4 ;
        RECT 65.380 0.000 66.380 75.180 ;
    END
    PORT
      LAYER Metal4 ;
        RECT 115.380 0.000 116.380 75.180 ;
    END
  END VGND
  PIN VPWR
    DIRECTION INOUT ;
    USE POWER ;
    PORT
      LAYER Metal4 ;
        RECT 12.380 0.000 13.380 75.180 ;
    END
    PORT
      LAYER Metal4 ;
        RECT 62.380 0.000 63.380 75.180 ;
    END
    PORT
      LAYER Metal4 ;
        RECT 112.380 0.000 113.380 75.180 ;
    END
  END VPWR
  OBS
      LAYER GatPoly ;
        RECT 2.880 3.630 133.920 68.190 ;
      LAYER Metal1 ;
        RECT 2.880 3.560 133.920 68.260 ;
      LAYER Metal2 ;
        RECT 2.295 74.570 4.870 74.905 ;
        RECT 5.690 74.570 11.590 74.905 ;
        RECT 12.410 74.570 18.310 74.905 ;
        RECT 19.130 74.570 25.030 74.905 ;
        RECT 25.850 74.570 31.750 74.905 ;
        RECT 32.570 74.570 38.470 74.905 ;
        RECT 39.290 74.570 45.190 74.905 ;
        RECT 46.010 74.570 51.910 74.905 ;
        RECT 52.730 74.570 58.630 74.905 ;
        RECT 59.450 74.570 65.350 74.905 ;
        RECT 66.170 74.570 72.070 74.905 ;
        RECT 72.890 74.570 78.790 74.905 ;
        RECT 79.610 74.570 85.510 74.905 ;
        RECT 86.330 74.570 92.230 74.905 ;
        RECT 93.050 74.570 98.950 74.905 ;
        RECT 99.770 74.570 105.670 74.905 ;
        RECT 106.490 74.570 112.390 74.905 ;
        RECT 113.210 74.570 119.110 74.905 ;
        RECT 119.930 74.570 125.830 74.905 ;
        RECT 126.650 74.570 132.550 74.905 ;
        RECT 2.295 0.610 133.065 74.570 ;
        RECT 2.810 0.275 2.950 0.610 ;
        RECT 3.770 0.275 3.910 0.610 ;
        RECT 4.730 0.275 4.870 0.610 ;
        RECT 5.690 0.275 8.710 0.610 ;
        RECT 9.530 0.275 9.670 0.610 ;
        RECT 10.490 0.275 10.630 0.610 ;
        RECT 11.450 0.275 11.590 0.610 ;
        RECT 12.410 0.275 12.550 0.610 ;
        RECT 13.370 0.275 13.510 0.610 ;
        RECT 14.330 0.275 14.470 0.610 ;
        RECT 15.290 0.275 15.430 0.610 ;
        RECT 16.250 0.275 20.230 0.610 ;
        RECT 21.050 0.275 21.190 0.610 ;
        RECT 22.010 0.275 22.150 0.610 ;
        RECT 22.970 0.275 23.110 0.610 ;
        RECT 23.930 0.275 24.070 0.610 ;
        RECT 24.890 0.275 25.030 0.610 ;
        RECT 25.850 0.275 25.990 0.610 ;
        RECT 26.810 0.275 26.950 0.610 ;
        RECT 27.770 0.275 33.670 0.610 ;
        RECT 34.490 0.275 34.630 0.610 ;
        RECT 35.450 0.275 35.590 0.610 ;
        RECT 36.410 0.275 36.550 0.610 ;
        RECT 37.370 0.275 37.510 0.610 ;
        RECT 38.330 0.275 38.470 0.610 ;
        RECT 39.290 0.275 39.430 0.610 ;
        RECT 40.250 0.275 40.390 0.610 ;
        RECT 41.210 0.275 41.350 0.610 ;
        RECT 42.170 0.275 42.310 0.610 ;
        RECT 43.130 0.275 43.270 0.610 ;
        RECT 44.090 0.275 44.230 0.610 ;
        RECT 45.050 0.275 45.190 0.610 ;
        RECT 46.010 0.275 46.150 0.610 ;
        RECT 46.970 0.275 47.110 0.610 ;
        RECT 47.930 0.275 48.070 0.610 ;
        RECT 48.890 0.275 54.790 0.610 ;
        RECT 55.610 0.275 55.750 0.610 ;
        RECT 56.570 0.275 56.710 0.610 ;
        RECT 57.530 0.275 57.670 0.610 ;
        RECT 58.490 0.275 61.510 0.610 ;
        RECT 62.330 0.275 62.470 0.610 ;
        RECT 63.290 0.275 63.430 0.610 ;
        RECT 64.250 0.275 64.390 0.610 ;
        RECT 65.210 0.275 65.350 0.610 ;
        RECT 66.170 0.275 66.310 0.610 ;
        RECT 67.130 0.275 67.270 0.610 ;
        RECT 68.090 0.275 68.230 0.610 ;
        RECT 69.050 0.275 73.030 0.610 ;
        RECT 73.850 0.275 73.990 0.610 ;
        RECT 74.810 0.275 74.950 0.610 ;
        RECT 75.770 0.275 75.910 0.610 ;
        RECT 76.730 0.275 76.870 0.610 ;
        RECT 77.690 0.275 77.830 0.610 ;
        RECT 78.650 0.275 78.790 0.610 ;
        RECT 79.610 0.275 79.750 0.610 ;
        RECT 80.570 0.275 87.430 0.610 ;
        RECT 88.250 0.275 88.390 0.610 ;
        RECT 89.210 0.275 89.350 0.610 ;
        RECT 90.170 0.275 90.310 0.610 ;
        RECT 91.130 0.275 91.270 0.610 ;
        RECT 92.090 0.275 92.230 0.610 ;
        RECT 93.050 0.275 93.190 0.610 ;
        RECT 94.010 0.275 94.150 0.610 ;
        RECT 94.970 0.275 95.110 0.610 ;
        RECT 95.930 0.275 96.070 0.610 ;
        RECT 96.890 0.275 97.030 0.610 ;
        RECT 97.850 0.275 97.990 0.610 ;
        RECT 98.810 0.275 98.950 0.610 ;
        RECT 99.770 0.275 99.910 0.610 ;
        RECT 100.730 0.275 100.870 0.610 ;
        RECT 101.690 0.275 101.830 0.610 ;
        RECT 102.650 0.275 112.390 0.610 ;
        RECT 113.210 0.275 113.350 0.610 ;
        RECT 114.170 0.275 114.310 0.610 ;
        RECT 115.130 0.275 115.270 0.610 ;
        RECT 116.090 0.275 116.230 0.610 ;
        RECT 117.050 0.275 117.190 0.610 ;
        RECT 118.010 0.275 118.150 0.610 ;
        RECT 118.970 0.275 119.110 0.610 ;
        RECT 119.930 0.275 120.070 0.610 ;
        RECT 120.890 0.275 121.030 0.610 ;
        RECT 121.850 0.275 121.990 0.610 ;
        RECT 122.810 0.275 122.950 0.610 ;
        RECT 123.770 0.275 123.910 0.610 ;
        RECT 124.730 0.275 124.870 0.610 ;
        RECT 125.690 0.275 125.830 0.610 ;
        RECT 126.650 0.275 126.790 0.610 ;
        RECT 127.610 0.275 127.750 0.610 ;
        RECT 128.570 0.275 128.710 0.610 ;
        RECT 129.530 0.275 129.670 0.610 ;
        RECT 130.490 0.275 130.630 0.610 ;
        RECT 131.450 0.275 133.065 0.610 ;
      LAYER Metal3 ;
        RECT 0.400 65.510 136.420 74.865 ;
        RECT 0.610 64.690 136.190 65.510 ;
        RECT 0.400 63.830 136.420 64.690 ;
        RECT 0.610 63.010 136.190 63.830 ;
        RECT 0.400 62.150 136.420 63.010 ;
        RECT 0.610 61.330 136.190 62.150 ;
        RECT 0.400 60.470 136.420 61.330 ;
        RECT 0.610 59.650 136.190 60.470 ;
        RECT 0.400 58.790 136.420 59.650 ;
        RECT 0.610 57.970 136.190 58.790 ;
        RECT 0.400 57.110 136.420 57.970 ;
        RECT 0.610 56.290 136.190 57.110 ;
        RECT 0.400 55.430 136.420 56.290 ;
        RECT 0.610 54.610 136.190 55.430 ;
        RECT 0.400 53.750 136.420 54.610 ;
        RECT 0.610 52.930 136.190 53.750 ;
        RECT 0.400 52.070 136.420 52.930 ;
        RECT 0.610 51.250 136.190 52.070 ;
        RECT 0.400 50.390 136.420 51.250 ;
        RECT 0.610 49.570 136.190 50.390 ;
        RECT 0.400 48.710 136.420 49.570 ;
        RECT 0.610 47.890 136.190 48.710 ;
        RECT 0.400 47.030 136.420 47.890 ;
        RECT 0.610 46.210 136.190 47.030 ;
        RECT 0.400 45.350 136.420 46.210 ;
        RECT 0.610 44.530 136.190 45.350 ;
        RECT 0.400 43.670 136.420 44.530 ;
        RECT 0.610 42.850 136.190 43.670 ;
        RECT 0.400 41.990 136.420 42.850 ;
        RECT 0.610 41.170 136.190 41.990 ;
        RECT 0.400 40.310 136.420 41.170 ;
        RECT 0.610 39.490 136.190 40.310 ;
        RECT 0.400 38.630 136.420 39.490 ;
        RECT 0.610 37.810 136.190 38.630 ;
        RECT 0.400 36.950 136.420 37.810 ;
        RECT 0.610 36.130 136.190 36.950 ;
        RECT 0.400 35.270 136.420 36.130 ;
        RECT 0.610 34.450 136.190 35.270 ;
        RECT 0.400 33.590 136.420 34.450 ;
        RECT 0.610 32.770 136.190 33.590 ;
        RECT 0.400 31.910 136.420 32.770 ;
        RECT 0.610 31.090 136.190 31.910 ;
        RECT 0.400 30.230 136.420 31.090 ;
        RECT 0.610 29.410 136.190 30.230 ;
        RECT 0.400 28.550 136.420 29.410 ;
        RECT 0.610 27.730 136.190 28.550 ;
        RECT 0.400 26.870 136.420 27.730 ;
        RECT 0.610 26.050 136.190 26.870 ;
        RECT 0.400 25.190 136.420 26.050 ;
        RECT 0.610 24.370 136.190 25.190 ;
        RECT 0.400 23.510 136.420 24.370 ;
        RECT 0.610 22.690 136.190 23.510 ;
        RECT 0.400 21.830 136.420 22.690 ;
        RECT 0.610 21.010 136.190 21.830 ;
        RECT 0.400 20.150 136.420 21.010 ;
        RECT 0.610 19.330 136.190 20.150 ;
        RECT 0.400 18.470 136.420 19.330 ;
        RECT 0.610 17.650 136.190 18.470 ;
        RECT 0.400 16.790 136.420 17.650 ;
        RECT 0.610 15.970 136.190 16.790 ;
        RECT 0.400 15.110 136.420 15.970 ;
        RECT 0.610 14.290 136.190 15.110 ;
        RECT 0.400 13.430 136.420 14.290 ;
        RECT 0.610 12.610 136.190 13.430 ;
        RECT 0.400 2.510 136.420 12.610 ;
        RECT 0.610 1.690 136.190 2.510 ;
        RECT 0.400 0.320 136.420 1.690 ;
      LAYER Metal4 ;
        RECT 11.210 1.955 12.170 74.905 ;
        RECT 13.590 1.955 15.170 74.905 ;
        RECT 16.590 1.955 62.170 74.905 ;
        RECT 63.590 1.955 65.170 74.905 ;
        RECT 66.590 1.955 112.170 74.905 ;
        RECT 113.590 1.955 115.170 74.905 ;
        RECT 116.590 1.955 131.350 74.905 ;
      LAYER TopMetal1 ;
        RECT 10.700 5.380 131.860 29.820 ;
  END
END N_term_RAM_IO
END LIBRARY

